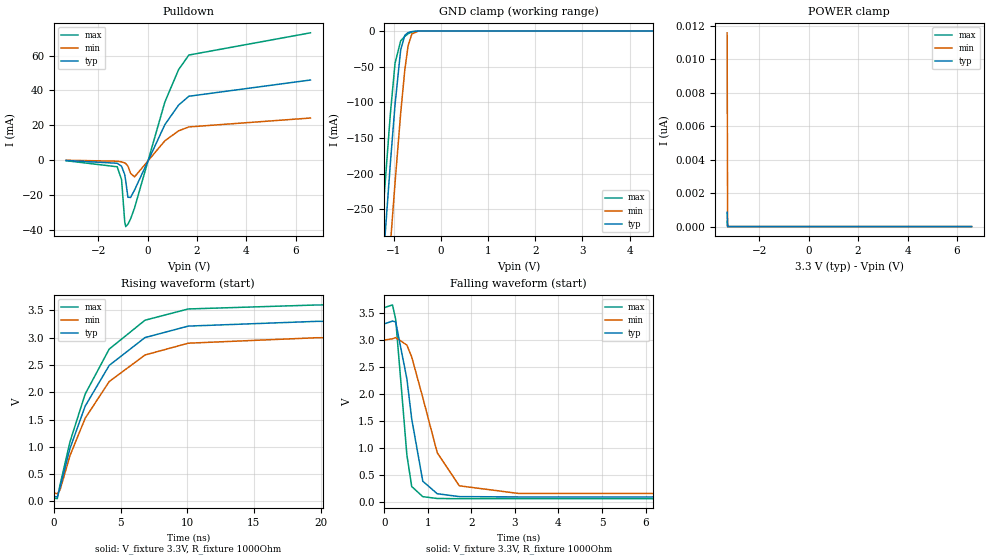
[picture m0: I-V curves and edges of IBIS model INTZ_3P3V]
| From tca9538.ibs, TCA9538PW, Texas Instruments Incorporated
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[Model]   INTZ_3P3V
Model_type   Open_drain
Polarity   Non-Inverting
Vmeas = 1.65
Vref = 3.3
Cref = 15pF
Rref = 1000
|   typ   min   max
|   (nom PVT)   (slow PVT)   (fast PVT)
C_comp   1.564p   1.477p   1.698p
|C_comp (ON state)   1.564p   1.477p   1.698p
|C_comp (OFF state)   1.568p   1.469p   1.788p
| Where   nom PVT is  Nominal Process, 3.3V, 27C
|   Fast PVT is Strong Process, 3.6V, -40C
|   Slow PVT is Weak Process, 3.0V, 125C
[Voltage Range]   3.3   3   3.6
[Temperature Range]   27   125   -40
[Pullup Reference]   3.3   3   3.6
[Pulldown Reference]   -0   -0   -0
[Power Clamp Reference]   3.3   3   3.6
[GND Clamp Reference]   -0   -0   -0
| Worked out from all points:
|   slope of the pulldown table from 0 to 0.495 V, typ, clamps not added: 32.9 ohm
|   GND clamp passes 1 mA (typ) near -0.64 V on its own axis
|   falling waveform, V_fixture 3.3V, R_fixture 1000Ohm: 20-80 % time 312ps typ, 576ps min, 207ps max; typ from 3.3 V to 0.094 V
|   rising waveform, V_fixture 3.3V, R_fixture 1000Ohm: 20-80 % time 3.84ns typ, 4.11ns min, 3.63ns max; typ from 0.094 V to 3.3 V
[Pulldown]
|   Voltage   I(typ)   I(min)   I(max)
-3.3V     -240.3uA   -104.9uA   -373.7uA
-1.231V   -1.834mA   -652uA     -3.85mA
-1.053V   -3.583mA   -1.033mA   -11.26mA
-924mV    -8.438mA   -1.673mA   -35.69mA
-884.4mV  -12.05mA   -2.025mA   -38.23mA
-795.3mV  -21.38mA   -3.466mA   -36.87mA
-686.4mV  -21.48mA   -7.648mA   -33.74mA
-528mV    -17.21mA   -9.663mA   -27.53mA
699.6mV   20.37mA    11.08mA    33.38mA
1.254V    31.58mA    16.79mA    51.95mA
1.67V     36.67mA    19.04mA    60.35mA
6.59V     46mA       24.16mA    73.12mA
[GND Clamp]
|   Voltage   I(typ)   I(min)   I(max)
-3.3V     -2.346A    -2.454A    -2.279A
-1.32V    -411.4mA   -527.6mA   -338.7mA
-1.27V    -365.1mA   -481.3mA   -292.4mA
-1.201V   -301mA     -417mA     -228.6mA
-1.073V   -185.6mA   -299.8mA   -116.1mA
-973.5mV  -103.1mA   -212.8mA   -45mA
-854.7mV  -26.54mA   -115.6mA   -13.88mA
-765.6mV  -5.748mA   -53.96mA   -7.462mA
-696.3mV  -2.245mA   -20.5mA    -3.835mA
-617.1mV  -729.5uA   -4.029mA   -1.265mA
-478.5mV  -54.82uA   -141.4uA   -70.74uA
6.59V     0A         0A         0A
[POWER Clamp]
|   Voltage   I(typ)   I(min)   I(max)
-3.3V     848.4pA    11.57nA    308.9pA
-3.28V    0A         0A         0A
-3.27V    0A         0A         0A
6.59V     0A         0A         0A
[Ramp]
R_load = 1000
|   typ   min   max
dV/dt_r   1.92355/3.8394e-09   1.70684/4.11134e-09   2.12299/3.6315e-09
dV/dt_f   1.92355/3.12494e-10   1.70684/5.75808e-10   2.123/2.07059e-10
[Falling Waveform]
V_fixture = 3.3V
V_fixture_min = 3V
V_fixture_max = 3.6V
R_fixture = 1000Ohm
C_fixture = 0F
|   Time   V(typ)   V(min)   V(max)
0s        3.3V       3V         3.6V
187.1ps   3.351V     3.023V     3.65V
260.5ps   3.334V     3.045V     3.38V
517.6ps   2.279V     2.906V     870.2mV
627.8ps   1.542V     2.686V     287.8mV
882.6ps   385.6mV    1.934V     99.58mV
1.214ns   153.5mV    915.2mV    65.36mV
1.722ns   100.3mV    300mV      61.64mV
3.088ns   94.01mV    158.4mV    61.64mV
99.9ns    94.09mV    155.3mV    61.67mV
[Rising Waveform]
V_fixture = 3.3V
V_fixture_min = 3V
V_fixture_max = 3.6V
R_fixture = 1000Ohm
C_fixture = 0F
|   Time   V(typ)   V(min)   V(max)
0s        94.09mV    155.3mV    61.67mV
260.5ps   80.4mV     139.8mV    50.21mV
465.3ps   255.1mV    209.6mV    303.1mV
1.214ns   971mV      840.9mV    1.095V
2.348ns   1.745V     1.523V     1.966V
4.153ns   2.492V     2.196V     2.791V
6.838ns   3.002V     2.683V     3.32V
10.08ns   3.212V     2.899V     3.526V
19.71ns   3.299V     2.999V     3.599V
99.9ns    3.3V       3V         3.6V
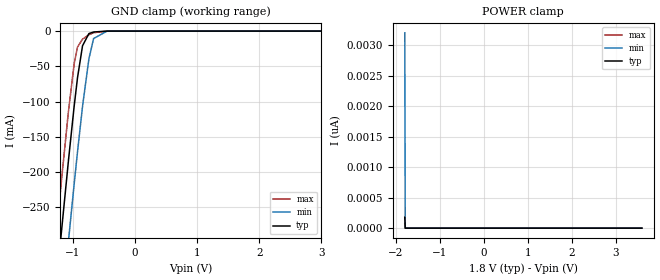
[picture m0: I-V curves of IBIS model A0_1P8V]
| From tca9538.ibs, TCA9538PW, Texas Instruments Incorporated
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[Model]   A0_1P8V
Model_type   Input
Vinl = 0.495
Vinh = 1.365
|   typ   min   max
|   (nom PVT)   (slow PVT)   (fast PVT)
C_comp   1.383p   1.344p   1.457p
| Where   nom PVT is  Nominal Process, 1.8V, 27C
|   Fast PVT is Strong Process, 1.95V, -40C
|   Slow PVT is Weak Process, 1.65V, 125C
[Voltage Range]   1.8   1.65   1.95
[Temperature Range]   27   125   -40
[Power Clamp Reference]   1.8   1.65   1.95
[GND Clamp Reference]   -0   -0   -0
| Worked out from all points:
|   GND clamp passes 1 mA (typ) near -0.64 V on its own axis
[GND Clamp]
|   Voltage   I(typ)   I(min)   I(max)
-1.8V     -871.3mA   -985.7mA   -800.1mA
-1.433V   -517.8mA   -633.7mA   -445.1mA
-1.222V   -319.9mA   -436mA     -247.2mA
-1.179V   -280.2mA   -396.1mA   -207.8mA
-1.071V   -183.6mA   -297.9mA   -113.8mA
-979.2mV  -106.6mA   -217.1mA   -46.46mA
-925.2mV  -66.11mA   -171.3mA   -22.65mA
-844.2mV  -20.82mA   -106.7mA   -11.41mA
-741.6mV  -3.52mA    -39.23mA   -5.3mA
-666mV    -1.292mA   -10.57mA   -2.286mA
-450mV    -25.05uA   -60.12uA   -30.74uA
3.595V    0A         0A         0A
[POWER Clamp]
|   Voltage   I(typ)   I(min)   I(max)
-1.8V     179.4pA    3.2nA      72.27pA
-1.789V   0A         0A         0A
-1.784V   0A         0A         0A
3.595V    0A         0A         0A
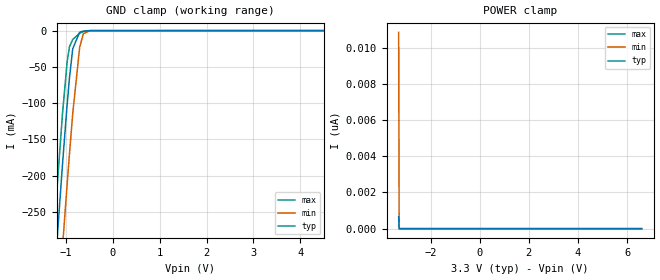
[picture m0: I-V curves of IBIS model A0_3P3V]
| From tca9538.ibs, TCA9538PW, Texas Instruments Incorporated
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[Model]   A0_3P3V
Model_type   Input
Vinl = .8
Vinh = 2
|   typ   min   max
|   (nom PVT)   (slow PVT)   (fast PVT)
C_comp   1.364p   1.306p   1.458p
| Where   nom PVT is  Nominal Process, 3.3V, 27C
|   Fast PVT is Strong Process, 3.6V, -40C
|   Slow PVT is Weak Process, 3.0V, 125C
[Voltage Range]   3.3   3   3.6
[Temperature Range]   27   125   -40
[Power Clamp Reference]   3.3   3   3.6
[GND Clamp Reference]   -0   -0   -0
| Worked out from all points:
|   GND clamp passes 1 mA (typ) near -0.65 V on its own axis
[GND Clamp]
|   Voltage   I(typ)   I(min)   I(max)
-3.3V     -2.345A    -2.454A    -2.279A
-1.32V    -411mA     -527.2mA   -338.2mA
-1.27V    -364.7mA   -480.9mA   -291.9mA
-1.201V   -300.6mA   -416.5mA   -228mA
-1.073V   -184.9mA   -299.3mA   -115mA
-973.5mV  -102.1mA   -212.2mA   -43.17mA
-924mV    -65.27mA   -170.3mA   -22.32mA
-854.7mV  -25.09mA   -114.7mA   -12.22mA
-706.2mV  -2.205mA   -22.91mA   -3.721mA
-627mV    -730.2uA   -4.348mA   -1.283mA
-488.4mV  -57.35uA   -147.9uA   -76.44uA
6.59V     0A         0A         0A
[POWER Clamp]
|   Voltage   I(typ)   I(min)   I(max)
-3.3V     664pA      10.84nA    162.7pA
-3.28V    0A         0A         0A
-3.27V    0A         0A         0A
6.59V     0A         0A         0A
